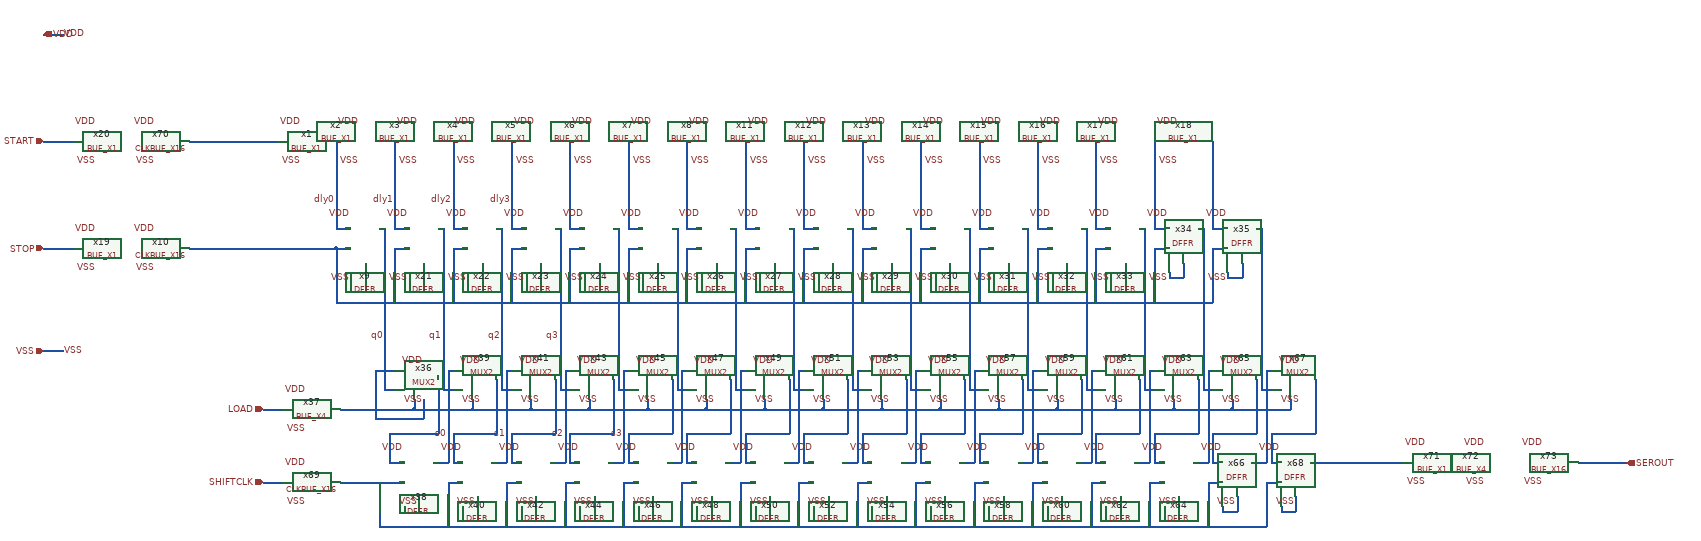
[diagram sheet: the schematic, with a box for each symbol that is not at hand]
v {xschem version=3.4.8RC file_version=1.2}
G {}
K {}
V {}
S {}
E {}
N -480 0 -420 0 {lab=START}
N -480 220 -420 220 {lab=STOP}
N 120 220 150 220 {lab=#net1}
N 120 -0 120 180 {lab=dly0}
N 120 180 150 180 {lab=dly0}
N 240 0 240 180 {lab=dly1}
N 240 180 270 180 {lab=dly1}
N 360 0 360 180 {lab=dly2}
N 360 180 390 180 {lab=dly2}
N 480 0 480 180 {lab=dly3}
N 480 180 510 180 {lab=dly3}
N 600 0 600 180 {lab=#net2}
N 600 180 630 180 {lab=#net2}
N 720 0 720 180 {lab=#net3}
N 720 180 750 180 {lab=#net3}
N 840 0 840 180 {lab=#net4}
N 840 180 870 180 {lab=#net4}
N 960 0 960 180 {lab=#net5}
N 960 180 990 180 {lab=#net5}
N 1080 0 1080 180 {lab=#net6}
N 1080 180 1110 180 {lab=#net6}
N 1200 0 1200 180 {lab=#net7}
N 1200 180 1230 180 {lab=#net7}
N 1320 0 1320 180 {lab=#net8}
N 1320 180 1350 180 {lab=#net8}
N 1440 0 1440 180 {lab=#net9}
N 1440 180 1470 180 {lab=#net9}
N 1560 0 1560 180 {lab=#net10}
N 1560 180 1590 180 {lab=#net10}
N 1680 0 1680 180 {lab=#net11}
N 1680 180 1710 180 {lab=#net11}
N 1800 0 1800 180 {lab=#net12}
N 1800 180 1830 180 {lab=#net12}
N 720 220 750 220 {lab=#net1}
N 720 220 720 330 {lab=#net1}
N 840 220 870 220 {lab=#net1}
N 840 220 840 330 {lab=#net1}
N 960 220 990 220 {lab=#net1}
N 960 220 960 330 {lab=#net1}
N 1080 220 1110 220 {lab=#net1}
N 1080 220 1080 330 {lab=#net1}
N 1200 220 1230 220 {lab=#net1}
N 1200 220 1200 330 {lab=#net1}
N 1320 220 1350 220 {lab=#net1}
N 1320 220 1320 330 {lab=#net1}
N 1440 220 1470 220 {lab=#net1}
N 1440 220 1440 330 {lab=#net1}
N 1560 220 1590 220 {lab=#net1}
N 1560 220 1560 330 {lab=#net1}
N 240 220 270 220 {lab=#net1}
N 240 220 240 330 {lab=#net1}
N 360 220 390 220 {lab=#net1}
N 360 220 360 330 {lab=#net1}
N 480 220 510 220 {lab=#net1}
N 480 220 480 330 {lab=#net1}
N 600 220 630 220 {lab=#net1}
N 600 220 600 330 {lab=#net1}
N 1680 220 1710 220 {lab=#net1}
N 1680 220 1680 330 {lab=#net1}
N 1800 220 1830 220 {lab=#net1}
N 1800 220 1800 330 {lab=#net1}
N 1920 0 1920 180 {lab=#net13}
N 1920 180 1950 180 {lab=#net13}
N 1920 220 1950 220 {lab=#net1}
N 1920 220 1920 330 {lab=#net1}
N 120 220 120 330 {lab=#net1}
N 120 330 1920 330 {lab=#net1}
N -180 220 120 220 {lab=#net1}
N 300 530 300 570 {lab=VSS}
N 200 570 300 570 {lab=VSS}
N 200 470 200 570 {lab=VSS}
N 200 470 240 470 {lab=VSS}
N 210 180 220 180 {lab=q0}
N 220 180 220 400 {lab=q0}
N 220 400 220 510 {lab=q0}
N 220 510 240 510 {lab=q0}
N 280 530 280 550 {lab=#net14}
N -30 550 10 550 {lab=LOAD}
N 130 550 280 550 {lab=#net14}
N 330 490 330 600 {lab=#net15}
N 230 600 330 600 {lab=#net15}
N 230 600 230 660 {lab=#net15}
N 230 660 260 660 {lab=#net15}
N 400 530 400 550 {lab=#net14}
N 330 180 340 180 {lab=q1}
N 340 180 340 510 {lab=q1}
N 350 700 380 700 {lab=#net16}
N 350 700 350 770 {lab=#net16}
N 350 770 350 790 {lab=#net16}
N 210 700 210 790 {lab=#net16}
N 340 510 360 510 {lab=q1}
N 350 470 360 470 {lab=s0}
N 350 470 350 660 {lab=s0}
N 320 660 350 660 {lab=s0}
N 280 550 400 550 {lab=#net14}
N 570 490 570 600 {lab=#net17}
N 520 530 520 550 {lab=#net14}
N 450 180 460 180 {lab=q2}
N 460 180 460 510 {lab=q2}
N 470 700 500 700 {lab=#net16}
N 470 700 470 770 {lab=#net16}
N 470 770 470 790 {lab=#net16}
N 480 660 500 660 {lab=#net17}
N 480 600 480 660 {lab=#net17}
N 480 600 570 600 {lab=#net17}
N 460 510 480 510 {lab=q2}
N 470 470 480 470 {lab=s1}
N 470 470 470 660 {lab=s1}
N 440 660 470 660 {lab=s1}
N 400 550 520 550 {lab=#net14}
N 690 490 690 600 {lab=#net18}
N 640 530 640 550 {lab=#net14}
N 570 180 580 180 {lab=q3}
N 580 180 580 510 {lab=q3}
N 590 700 620 700 {lab=#net16}
N 590 700 590 770 {lab=#net16}
N 590 770 590 790 {lab=#net16}
N 600 660 620 660 {lab=#net18}
N 600 600 600 660 {lab=#net18}
N 600 600 690 600 {lab=#net18}
N 580 510 600 510 {lab=q3}
N 590 470 600 470 {lab=s2}
N 590 470 590 660 {lab=s2}
N 560 660 590 660 {lab=s2}
N 520 550 640 550 {lab=#net14}
N 810 490 810 600 {lab=#net19}
N 760 530 760 550 {lab=#net14}
N 690 180 700 180 {lab=#net20}
N 700 180 700 510 {lab=#net20}
N 710 700 740 700 {lab=#net16}
N 710 700 710 770 {lab=#net16}
N 710 770 710 790 {lab=#net16}
N 720 660 740 660 {lab=#net19}
N 720 600 720 660 {lab=#net19}
N 720 600 810 600 {lab=#net19}
N 700 510 720 510 {lab=#net20}
N 710 470 720 470 {lab=s3}
N 710 470 710 660 {lab=s3}
N 680 660 710 660 {lab=s3}
N 640 550 760 550 {lab=#net14}
N 930 490 930 600 {lab=#net21}
N 880 530 880 550 {lab=#net14}
N 810 180 820 180 {lab=#net22}
N 820 180 820 510 {lab=#net22}
N 830 700 860 700 {lab=#net16}
N 830 700 830 770 {lab=#net16}
N 830 770 830 790 {lab=#net16}
N 840 660 860 660 {lab=#net21}
N 840 600 840 660 {lab=#net21}
N 840 600 930 600 {lab=#net21}
N 820 510 840 510 {lab=#net22}
N 830 470 840 470 {lab=#net23}
N 830 470 830 660 {lab=#net23}
N 800 660 830 660 {lab=#net23}
N 760 550 880 550 {lab=#net14}
N 1050 490 1050 600 {lab=#net24}
N 1000 530 1000 550 {lab=#net14}
N 930 180 940 180 {lab=#net25}
N 940 180 940 510 {lab=#net25}
N 950 700 980 700 {lab=#net16}
N 950 700 950 770 {lab=#net16}
N 950 770 950 790 {lab=#net16}
N 960 660 980 660 {lab=#net24}
N 960 600 960 660 {lab=#net24}
N 960 600 1050 600 {lab=#net24}
N 940 510 960 510 {lab=#net25}
N 950 470 960 470 {lab=#net26}
N 950 470 950 660 {lab=#net26}
N 920 660 950 660 {lab=#net26}
N 880 550 1000 550 {lab=#net14}
N 1170 490 1170 600 {lab=#net27}
N 1120 530 1120 550 {lab=#net14}
N 1050 180 1060 180 {lab=#net28}
N 1060 180 1060 510 {lab=#net28}
N 1070 700 1100 700 {lab=#net16}
N 1070 700 1070 770 {lab=#net16}
N 1070 770 1070 790 {lab=#net16}
N 1080 660 1100 660 {lab=#net27}
N 1080 600 1080 660 {lab=#net27}
N 1080 600 1170 600 {lab=#net27}
N 1060 510 1080 510 {lab=#net28}
N 1070 470 1080 470 {lab=#net29}
N 1070 470 1070 660 {lab=#net29}
N 1040 660 1070 660 {lab=#net29}
N 1000 550 1120 550 {lab=#net14}
N 1290 490 1290 600 {lab=#net30}
N 1240 530 1240 550 {lab=#net14}
N 1170 180 1180 180 {lab=#net31}
N 1180 180 1180 510 {lab=#net31}
N 1190 700 1220 700 {lab=#net16}
N 1190 700 1190 770 {lab=#net16}
N 1190 770 1190 790 {lab=#net16}
N 1200 660 1220 660 {lab=#net30}
N 1200 600 1200 660 {lab=#net30}
N 1200 600 1290 600 {lab=#net30}
N 1180 510 1200 510 {lab=#net31}
N 1190 470 1200 470 {lab=#net32}
N 1190 470 1190 660 {lab=#net32}
N 1160 660 1190 660 {lab=#net32}
N 1120 550 1240 550 {lab=#net14}
N 1410 490 1410 600 {lab=#net33}
N 1360 530 1360 550 {lab=#net14}
N 1290 180 1300 180 {lab=#net34}
N 1300 180 1300 510 {lab=#net34}
N 1310 700 1340 700 {lab=#net16}
N 1310 700 1310 770 {lab=#net16}
N 1310 770 1310 790 {lab=#net16}
N 1320 660 1340 660 {lab=#net33}
N 1320 600 1320 660 {lab=#net33}
N 1320 600 1410 600 {lab=#net33}
N 1300 510 1320 510 {lab=#net34}
N 1310 470 1320 470 {lab=#net35}
N 1310 470 1310 660 {lab=#net35}
N 1280 660 1310 660 {lab=#net35}
N 1240 550 1360 550 {lab=#net14}
N 1530 490 1530 600 {lab=#net36}
N 1480 530 1480 550 {lab=#net14}
N 1410 180 1420 180 {lab=#net37}
N 1420 180 1420 510 {lab=#net37}
N 1430 700 1460 700 {lab=#net16}
N 1430 700 1430 770 {lab=#net16}
N 1430 770 1430 790 {lab=#net16}
N 1440 660 1460 660 {lab=#net36}
N 1440 600 1440 660 {lab=#net36}
N 1440 600 1530 600 {lab=#net36}
N 1420 510 1440 510 {lab=#net37}
N 1430 470 1440 470 {lab=#net38}
N 1430 470 1430 660 {lab=#net38}
N 1400 660 1430 660 {lab=#net38}
N 1360 550 1480 550 {lab=#net14}
N 1650 490 1650 600 {lab=#net39}
N 1600 530 1600 550 {lab=#net14}
N 1530 180 1540 180 {lab=#net40}
N 1540 180 1540 510 {lab=#net40}
N 1550 700 1580 700 {lab=#net16}
N 1550 700 1550 770 {lab=#net16}
N 1550 770 1550 790 {lab=#net16}
N 1560 660 1580 660 {lab=#net39}
N 1560 600 1560 660 {lab=#net39}
N 1560 600 1650 600 {lab=#net39}
N 1540 510 1560 510 {lab=#net40}
N 1550 470 1560 470 {lab=#net41}
N 1550 470 1550 660 {lab=#net41}
N 1520 660 1550 660 {lab=#net41}
N 1480 550 1600 550 {lab=#net14}
N 1770 490 1770 600 {lab=#net42}
N 1720 530 1720 550 {lab=#net14}
N 1650 180 1660 180 {lab=#net43}
N 1660 180 1660 510 {lab=#net43}
N 1670 700 1700 700 {lab=#net16}
N 1670 700 1670 770 {lab=#net16}
N 1670 770 1670 790 {lab=#net16}
N 1680 660 1700 660 {lab=#net42}
N 1680 600 1680 660 {lab=#net42}
N 1680 600 1770 600 {lab=#net42}
N 1660 510 1680 510 {lab=#net43}
N 1670 470 1680 470 {lab=#net44}
N 1670 470 1670 660 {lab=#net44}
N 1640 660 1670 660 {lab=#net44}
N 1600 550 1720 550 {lab=#net14}
N 1890 490 1890 600 {lab=#net45}
N 1840 530 1840 550 {lab=#net14}
N 1770 180 1780 180 {lab=#net46}
N 1780 180 1780 510 {lab=#net46}
N 1790 700 1820 700 {lab=#net16}
N 1790 700 1790 770 {lab=#net16}
N 1790 770 1790 790 {lab=#net16}
N 1800 660 1820 660 {lab=#net45}
N 1800 600 1800 660 {lab=#net45}
N 1800 600 1890 600 {lab=#net45}
N 1780 510 1800 510 {lab=#net46}
N 1790 470 1800 470 {lab=#net47}
N 1790 470 1790 660 {lab=#net47}
N 1760 660 1790 660 {lab=#net47}
N 1720 550 1840 550 {lab=#net14}
N 2010 490 2010 600 {lab=#net48}
N 1960 530 1960 550 {lab=#net14}
N 1890 180 1900 180 {lab=#net49}
N 1900 180 1900 510 {lab=#net49}
N 1910 700 1940 700 {lab=#net16}
N 1910 700 1910 770 {lab=#net16}
N 1910 770 1910 790 {lab=#net16}
N 1920 660 1940 660 {lab=#net48}
N 1920 600 1920 660 {lab=#net48}
N 1920 600 2010 600 {lab=#net48}
N 1900 510 1920 510 {lab=#net49}
N 1910 470 1920 470 {lab=#net50}
N 1910 470 1910 660 {lab=#net50}
N 1880 660 1910 660 {lab=#net50}
N 1840 550 1960 550 {lab=#net14}
N 2130 490 2130 600 {lab=#net51}
N 2080 530 2080 550 {lab=#net14}
N 2010 180 2020 180 {lab=#net52}
N 2020 180 2020 510 {lab=#net52}
N 2030 700 2060 700 {lab=#net16}
N 2030 700 2030 770 {lab=#net16}
N 2030 770 2030 790 {lab=#net16}
N 2040 660 2060 660 {lab=#net51}
N 2040 600 2040 660 {lab=#net51}
N 2040 600 2130 600 {lab=#net51}
N 2020 510 2040 510 {lab=#net52}
N 2030 470 2040 470 {lab=#net53}
N 2030 470 2030 660 {lab=#net53}
N 2000 660 2030 660 {lab=#net53}
N 1960 550 2080 550 {lab=#net14}
N 210 790 2030 790 {lab=#net16}
N 450 490 450 600 {lab=#net54}
N 360 600 450 600 {lab=#net54}
N 360 600 360 660 {lab=#net54}
N 360 660 380 660 {lab=#net54}
N 140 700 260 700 {lab=#net16}
N 130 700 140 700 {lab=#net16}
N -30 700 10 700 {lab=SHIFTCLK}
N 2120 660 2310 660 {lab=#net55}
N 2670 660 2770 660 {lab=SEROUT}
N -180 0 0 0 {lab=#net56}
N 180 250 180 280 {lab=VSS}
N 150 280 180 280 {lab=VSS}
N 150 270 150 280 {lab=VSS}
N 300 250 300 280 {lab=VSS}
N 270 280 300 280 {lab=VSS}
N 270 270 270 280 {lab=VSS}
N 420 250 420 280 {lab=VSS}
N 390 280 420 280 {lab=VSS}
N 390 270 390 280 {lab=VSS}
N 540 250 540 280 {lab=VSS}
N 510 280 540 280 {lab=VSS}
N 510 270 510 280 {lab=VSS}
N 660 250 660 280 {lab=VSS}
N 630 280 660 280 {lab=VSS}
N 630 270 630 280 {lab=VSS}
N 780 250 780 280 {lab=VSS}
N 750 280 780 280 {lab=VSS}
N 750 270 750 280 {lab=VSS}
N 900 250 900 280 {lab=VSS}
N 870 280 900 280 {lab=VSS}
N 870 270 870 280 {lab=VSS}
N 1020 250 1020 280 {lab=VSS}
N 990 280 1020 280 {lab=VSS}
N 990 270 990 280 {lab=VSS}
N 1140 250 1140 280 {lab=VSS}
N 1110 280 1140 280 {lab=VSS}
N 1110 270 1110 280 {lab=VSS}
N 1260 250 1260 280 {lab=VSS}
N 1230 280 1260 280 {lab=VSS}
N 1230 270 1230 280 {lab=VSS}
N 1380 250 1380 280 {lab=VSS}
N 1350 280 1380 280 {lab=VSS}
N 1350 270 1350 280 {lab=VSS}
N 1500 250 1500 280 {lab=VSS}
N 1470 280 1500 280 {lab=VSS}
N 1470 270 1470 280 {lab=VSS}
N 1620 250 1620 280 {lab=VSS}
N 1590 280 1620 280 {lab=VSS}
N 1590 270 1590 280 {lab=VSS}
N 1740 250 1740 280 {lab=VSS}
N 1710 280 1740 280 {lab=VSS}
N 1710 270 1710 280 {lab=VSS}
N 1860 250 1860 280 {lab=VSS}
N 1830 280 1860 280 {lab=VSS}
N 1830 270 1830 280 {lab=VSS}
N 1980 250 1980 280 {lab=VSS}
N 1950 280 1980 280 {lab=VSS}
N 1950 270 1950 280 {lab=VSS}
N 290 730 290 760 {lab=VSS}
N 260 760 290 760 {lab=VSS}
N 260 750 260 760 {lab=VSS}
N 410 730 410 760 {lab=VSS}
N 380 760 410 760 {lab=VSS}
N 380 750 380 760 {lab=VSS}
N 530 730 530 760 {lab=VSS}
N 500 760 530 760 {lab=VSS}
N 500 750 500 760 {lab=VSS}
N 650 730 650 760 {lab=VSS}
N 620 760 650 760 {lab=VSS}
N 620 750 620 760 {lab=VSS}
N 770 730 770 760 {lab=VSS}
N 740 760 770 760 {lab=VSS}
N 740 750 740 760 {lab=VSS}
N 890 730 890 760 {lab=VSS}
N 860 760 890 760 {lab=VSS}
N 860 750 860 760 {lab=VSS}
N 1010 730 1010 760 {lab=VSS}
N 980 760 1010 760 {lab=VSS}
N 980 750 980 760 {lab=VSS}
N 1130 730 1130 760 {lab=VSS}
N 1100 760 1130 760 {lab=VSS}
N 1100 750 1100 760 {lab=VSS}
N 1250 730 1250 760 {lab=VSS}
N 1220 760 1250 760 {lab=VSS}
N 1220 750 1220 760 {lab=VSS}
N 1370 730 1370 760 {lab=VSS}
N 1340 760 1370 760 {lab=VSS}
N 1340 750 1340 760 {lab=VSS}
N 1490 730 1490 760 {lab=VSS}
N 1460 760 1490 760 {lab=VSS}
N 1460 750 1460 760 {lab=VSS}
N 1610 730 1610 760 {lab=VSS}
N 1580 760 1610 760 {lab=VSS}
N 1580 750 1580 760 {lab=VSS}
N 1730 730 1730 760 {lab=VSS}
N 1700 760 1730 760 {lab=VSS}
N 1700 750 1700 760 {lab=VSS}
N 1850 730 1850 760 {lab=VSS}
N 1820 760 1850 760 {lab=VSS}
N 1820 750 1820 760 {lab=VSS}
N 1970 730 1970 760 {lab=VSS}
N 1940 760 1970 760 {lab=VSS}
N 1940 750 1940 760 {lab=VSS}
N 2090 730 2090 760 {lab=VSS}
N 2060 760 2090 760 {lab=VSS}
N 2060 750 2060 760 {lab=VSS}
N -480 -220 -440 -220 {lab=VDD}
N -480 430 -440 430 {lab=VSS}
C {TR-1um_5_stdcell/BUF_X1.sym} 20 0 0 0 {name=x1}
C {TR-1um_5_stdcell/BUF_X1.sym} 140 0 0 0 {name=x2}
C {TR-1um_5_stdcell/BUF_X1.sym} 260 0 0 0 {name=x3}
C {TR-1um_5_stdcell/BUF_X1.sym} 380 0 0 0 {name=x4}
C {TR-1um_5_stdcell/BUF_X1.sym} 500 0 0 0 {name=x5}
C {TR-1um_5_stdcell/BUF_X1.sym} 620 0 0 0 {name=x6}
C {TR-1um_5_stdcell/BUF_X1.sym} 740 0 0 0 {name=x7}
C {TR-1um_5_stdcell/BUF_X1.sym} 860 0 0 0 {name=x8}
C {TR-1um_5_stdcell/DFFR.sym} 180 210 0 0 {name=x9}
C {TR-1um_5_stdcell/CLKBUF_X16.sym} -280 220 0 0 {name=x10}
C {TR-1um_5_stdcell/BUF_X1.sym} 980 0 0 0 {name=x11}
C {TR-1um_5_stdcell/BUF_X1.sym} 1100 0 0 0 {name=x12}
C {TR-1um_5_stdcell/BUF_X1.sym} 1220 0 0 0 {name=x13}
C {TR-1um_5_stdcell/BUF_X1.sym} 1340 0 0 0 {name=x14}
C {TR-1um_5_stdcell/BUF_X1.sym} 1460 0 0 0 {name=x15}
C {TR-1um_5_stdcell/BUF_X1.sym} 1580 0 0 0 {name=x16}
C {TR-1um_5_stdcell/BUF_X1.sym} 1700 0 0 0 {name=x17}
C {TR-1um_5_stdcell/BUF_X1.sym} 1820 0 0 0 {name=x18}
C {TR-1um_5_stdcell/BUF_X1.sym} -400 220 0 0 {name=x19}
C {TR-1um_5_stdcell/BUF_X1.sym} -400 0 0 0 {name=x20}
C {devices/ipin.sym} -480 0 0 0 {name=p10 lab=START}
C {devices/ipin.sym} -480 220 0 0 {name=p1 lab=STOP}
C {TR-1um_5_stdcell/DFFR.sym} 300 210 0 0 {name=x21}
C {TR-1um_5_stdcell/DFFR.sym} 420 210 0 0 {name=x22}
C {TR-1um_5_stdcell/DFFR.sym} 540 210 0 0 {name=x23}
C {TR-1um_5_stdcell/DFFR.sym} 660 210 0 0 {name=x24}
C {TR-1um_5_stdcell/DFFR.sym} 780 210 0 0 {name=x25}
C {TR-1um_5_stdcell/DFFR.sym} 900 210 0 0 {name=x26}
C {TR-1um_5_stdcell/DFFR.sym} 1020 210 0 0 {name=x27}
C {TR-1um_5_stdcell/DFFR.sym} 1140 210 0 0 {name=x28}
C {TR-1um_5_stdcell/DFFR.sym} 1260 210 0 0 {name=x29}
C {TR-1um_5_stdcell/DFFR.sym} 1380 210 0 0 {name=x30}
C {TR-1um_5_stdcell/DFFR.sym} 1500 210 0 0 {name=x31}
C {TR-1um_5_stdcell/DFFR.sym} 1620 210 0 0 {name=x32}
C {TR-1um_5_stdcell/DFFR.sym} 1740 210 0 0 {name=x33}
C {TR-1um_5_stdcell/DFFR.sym} 1860 210 0 0 {name=x34}
C {TR-1um_5_stdcell/DFFR.sym} 1980 210 0 0 {name=x35}
C {devices/iopin.sym} -480 -220 0 1 {name=p17 lab=VDD}
C {devices/iopin.sym} -480 430 2 0 {name=p6 lab=VSS}
C {devices/ipin.sym} -30 700 0 0 {name=p2 lab=SHIFTCLK}
C {devices/opin.sym} 2770 660 0 0 {name=p16 lab=SEROUT}
C {TR-1um_5_stdcell/MUX2.sym} 260 490 0 0 {name=x36}
C {devices/ipin.sym} -30 550 0 0 {name=p3 lab=LOAD}
C {TR-1um_5_stdcell/DFFR.sym} 290 690 0 0 {name=x38}
C {TR-1um_5_stdcell/MUX2.sym} 380 490 0 0 {name=x39}
C {TR-1um_5_stdcell/DFFR.sym} 410 690 0 0 {name=x40}
C {TR-1um_5_stdcell/MUX2.sym} 500 490 0 0 {name=x41}
C {TR-1um_5_stdcell/DFFR.sym} 530 690 0 0 {name=x42}
C {TR-1um_5_stdcell/MUX2.sym} 620 490 0 0 {name=x43}
C {TR-1um_5_stdcell/DFFR.sym} 650 690 0 0 {name=x44}
C {TR-1um_5_stdcell/MUX2.sym} 740 490 0 0 {name=x45}
C {TR-1um_5_stdcell/DFFR.sym} 770 690 0 0 {name=x46}
C {TR-1um_5_stdcell/MUX2.sym} 860 490 0 0 {name=x47}
C {TR-1um_5_stdcell/DFFR.sym} 890 690 0 0 {name=x48}
C {TR-1um_5_stdcell/MUX2.sym} 980 490 0 0 {name=x49}
C {TR-1um_5_stdcell/DFFR.sym} 1010 690 0 0 {name=x50}
C {TR-1um_5_stdcell/MUX2.sym} 1100 490 0 0 {name=x51}
C {TR-1um_5_stdcell/DFFR.sym} 1130 690 0 0 {name=x52}
C {TR-1um_5_stdcell/MUX2.sym} 1220 490 0 0 {name=x53}
C {TR-1um_5_stdcell/DFFR.sym} 1250 690 0 0 {name=x54}
C {TR-1um_5_stdcell/MUX2.sym} 1340 490 0 0 {name=x55}
C {TR-1um_5_stdcell/DFFR.sym} 1370 690 0 0 {name=x56}
C {TR-1um_5_stdcell/MUX2.sym} 1460 490 0 0 {name=x57}
C {TR-1um_5_stdcell/DFFR.sym} 1490 690 0 0 {name=x58}
C {TR-1um_5_stdcell/MUX2.sym} 1580 490 0 0 {name=x59}
C {TR-1um_5_stdcell/DFFR.sym} 1610 690 0 0 {name=x60}
C {TR-1um_5_stdcell/MUX2.sym} 1700 490 0 0 {name=x61}
C {TR-1um_5_stdcell/DFFR.sym} 1730 690 0 0 {name=x62}
C {TR-1um_5_stdcell/MUX2.sym} 1820 490 0 0 {name=x63}
C {TR-1um_5_stdcell/DFFR.sym} 1850 690 0 0 {name=x64}
C {TR-1um_5_stdcell/MUX2.sym} 1940 490 0 0 {name=x65}
C {TR-1um_5_stdcell/DFFR.sym} 1970 690 0 0 {name=x66}
C {TR-1um_5_stdcell/MUX2.sym} 2060 490 0 0 {name=x67}
C {TR-1um_5_stdcell/DFFR.sym} 2090 690 0 0 {name=x68}
C {TR-1um_5_stdcell/BUF_X4.sym} 30 550 0 0 {name=x37}
C {TR-1um_5_stdcell/CLKBUF_X16.sym} 30 700 0 0 {name=x69}
C {TR-1um_5_stdcell/CLKBUF_X16.sym} -280 0 0 0 {name=x70}
C {TR-1um_5_stdcell/BUF_X1.sym} 2330 660 0 0 {name=x71}
C {TR-1um_5_stdcell/BUF_X4.sym} 2450 660 0 0 {name=x72}
C {TR-1um_5_stdcell/BUF_X16.sym} 2570 660 0 0 {name=x73}
C {devices/lab_pin.sym} -440 -220 2 0 {name=p4 sig_type=std_logic lab=VDD}
C {devices/lab_pin.sym} -440 430 2 0 {name=p77 sig_type=std_logic lab=VSS}
C {devices/lab_pin.sym} -370 -40 1 0 {name=p146 sig_type=std_logic lab=VDD}
C {devices/lab_pin.sym} -250 -40 1 0 {name=p147 sig_type=std_logic lab=VDD}
C {devices/lab_pin.sym} -370 40 3 0 {name=p148 sig_type=std_logic lab=VSS}
C {devices/lab_pin.sym} -250 40 3 0 {name=p149 sig_type=std_logic lab=VSS}
C {devices/lab_pin.sym} -370 180 1 0 {name=p7 sig_type=std_logic lab=VDD}
C {devices/lab_pin.sym} -250 180 1 0 {name=p78 sig_type=std_logic lab=VDD}
C {devices/lab_pin.sym} -370 260 3 0 {name=p150 sig_type=std_logic lab=VSS}
C {devices/lab_pin.sym} -250 260 3 0 {name=p151 sig_type=std_logic lab=VSS}
C {devices/lab_pin.sym} 2360 620 1 0 {name=p152 sig_type=std_logic lab=VDD}
C {devices/lab_pin.sym} 2360 700 3 0 {name=p153 sig_type=std_logic lab=VSS}
C {devices/lab_pin.sym} 2480 620 1 0 {name=p74 sig_type=std_logic lab=VDD}
C {devices/lab_pin.sym} 2480 700 3 0 {name=p75 sig_type=std_logic lab=VSS}
C {devices/lab_pin.sym} 2600 620 1 0 {name=p76 sig_type=std_logic lab=VDD}
C {devices/lab_pin.sym} 2600 700 3 0 {name=p143 sig_type=std_logic lab=VSS}
C {devices/lab_pin.sym} 50 -40 1 0 {name=p5 sig_type=std_logic lab=VDD}
C {devices/lab_pin.sym} 170 -40 1 0 {name=p9 sig_type=std_logic lab=VDD}
C {devices/lab_pin.sym} 290 -40 1 0 {name=p11 sig_type=std_logic lab=VDD}
C {devices/lab_pin.sym} 410 -40 1 0 {name=p12 sig_type=std_logic lab=VDD}
C {devices/lab_pin.sym} 530 -40 1 0 {name=p13 sig_type=std_logic lab=VDD}
C {devices/lab_pin.sym} 650 -40 1 0 {name=p14 sig_type=std_logic lab=VDD}
C {devices/lab_pin.sym} 770 -40 1 0 {name=p15 sig_type=std_logic lab=VDD}
C {devices/lab_pin.sym} 890 -40 1 0 {name=p18 sig_type=std_logic lab=VDD}
C {devices/lab_pin.sym} 1490 -40 1 0 {name=p19 sig_type=std_logic lab=VDD}
C {devices/lab_pin.sym} 1610 -40 1 0 {name=p20 sig_type=std_logic lab=VDD}
C {devices/lab_pin.sym} 1730 -40 1 0 {name=p21 sig_type=std_logic lab=VDD}
C {devices/lab_pin.sym} 1850 -40 1 0 {name=p22 sig_type=std_logic lab=VDD}
C {devices/lab_pin.sym} 1010 -40 1 0 {name=p23 sig_type=std_logic lab=VDD}
C {devices/lab_pin.sym} 1130 -40 1 0 {name=p24 sig_type=std_logic lab=VDD}
C {devices/lab_pin.sym} 1250 -40 1 0 {name=p25 sig_type=std_logic lab=VDD}
C {devices/lab_pin.sym} 1370 -40 1 0 {name=p26 sig_type=std_logic lab=VDD}
C {devices/lab_pin.sym} 1950 150 1 0 {name=p38 sig_type=std_logic lab=VDD}
C {devices/lab_pin.sym} 150 280 3 0 {name=p95 sig_type=std_logic lab=VSS}
C {devices/lab_pin.sym} 270 280 3 0 {name=p96 sig_type=std_logic lab=VSS}
C {devices/lab_pin.sym} 390 280 3 0 {name=p97 sig_type=std_logic lab=VSS}
C {devices/lab_pin.sym} 510 280 3 0 {name=p98 sig_type=std_logic lab=VSS}
C {devices/lab_pin.sym} 630 280 3 0 {name=p99 sig_type=std_logic lab=VSS}
C {devices/lab_pin.sym} 750 280 3 0 {name=p100 sig_type=std_logic lab=VSS}
C {devices/lab_pin.sym} 870 280 3 0 {name=p101 sig_type=std_logic lab=VSS}
C {devices/lab_pin.sym} 990 280 3 0 {name=p102 sig_type=std_logic lab=VSS}
C {devices/lab_pin.sym} 1110 280 3 0 {name=p103 sig_type=std_logic lab=VSS}
C {devices/lab_pin.sym} 1230 280 3 0 {name=p104 sig_type=std_logic lab=VSS}
C {devices/lab_pin.sym} 1350 280 3 0 {name=p105 sig_type=std_logic lab=VSS}
C {devices/lab_pin.sym} 1470 280 3 0 {name=p106 sig_type=std_logic lab=VSS}
C {devices/lab_pin.sym} 1590 280 3 0 {name=p107 sig_type=std_logic lab=VSS}
C {devices/lab_pin.sym} 1710 280 3 0 {name=p108 sig_type=std_logic lab=VSS}
C {devices/lab_pin.sym} 1830 280 3 0 {name=p109 sig_type=std_logic lab=VSS}
C {devices/lab_pin.sym} 1950 280 3 0 {name=p110 sig_type=std_logic lab=VSS}
C {devices/lab_pin.sym} 300 450 1 0 {name=p42 sig_type=std_logic lab=VDD}
C {devices/lab_pin.sym} 420 450 1 0 {name=p43 sig_type=std_logic lab=VDD}
C {devices/lab_pin.sym} 540 450 1 0 {name=p44 sig_type=std_logic lab=VDD}
C {devices/lab_pin.sym} 660 450 1 0 {name=p45 sig_type=std_logic lab=VDD}
C {devices/lab_pin.sym} 780 450 1 0 {name=p46 sig_type=std_logic lab=VDD}
C {devices/lab_pin.sym} 900 450 1 0 {name=p47 sig_type=std_logic lab=VDD}
C {devices/lab_pin.sym} 1020 450 1 0 {name=p48 sig_type=std_logic lab=VDD}
C {devices/lab_pin.sym} 1140 450 1 0 {name=p49 sig_type=std_logic lab=VDD}
C {devices/lab_pin.sym} 1740 450 1 0 {name=p50 sig_type=std_logic lab=VDD}
C {devices/lab_pin.sym} 1860 450 1 0 {name=p51 sig_type=std_logic lab=VDD}
C {devices/lab_pin.sym} 1980 450 1 0 {name=p52 sig_type=std_logic lab=VDD}
C {devices/lab_pin.sym} 2100 450 1 0 {name=p53 sig_type=std_logic lab=VDD}
C {devices/lab_pin.sym} 1260 450 1 0 {name=p54 sig_type=std_logic lab=VDD}
C {devices/lab_pin.sym} 1380 450 1 0 {name=p55 sig_type=std_logic lab=VDD}
C {devices/lab_pin.sym} 1500 450 1 0 {name=p56 sig_type=std_logic lab=VDD}
C {devices/lab_pin.sym} 1620 450 1 0 {name=p144 sig_type=std_logic lab=VDD}
C {devices/lab_pin.sym} 60 510 1 0 {name=p57 sig_type=std_logic lab=VDD}
C {devices/lab_pin.sym} 60 590 3 0 {name=p145 sig_type=std_logic lab=VSS}
C {devices/lab_pin.sym} 60 660 1 0 {name=p154 sig_type=std_logic lab=VDD}
C {devices/lab_pin.sym} 60 740 3 0 {name=p155 sig_type=std_logic lab=VSS}
C {devices/lab_pin.sym} 50 40 3 0 {name=p58 sig_type=std_logic lab=VSS}
C {devices/lab_pin.sym} 150 150 1 0 {name=p59 sig_type=std_logic lab=VDD}
C {devices/lab_pin.sym} 270 150 1 0 {name=p60 sig_type=std_logic lab=VDD}
C {devices/lab_pin.sym} 390 150 1 0 {name=p61 sig_type=std_logic lab=VDD}
C {devices/lab_pin.sym} 510 150 1 0 {name=p62 sig_type=std_logic lab=VDD}
C {devices/lab_pin.sym} 630 150 1 0 {name=p63 sig_type=std_logic lab=VDD}
C {devices/lab_pin.sym} 750 150 1 0 {name=p64 sig_type=std_logic lab=VDD}
C {devices/lab_pin.sym} 870 150 1 0 {name=p65 sig_type=std_logic lab=VDD}
C {devices/lab_pin.sym} 990 150 1 0 {name=p66 sig_type=std_logic lab=VDD}
C {devices/lab_pin.sym} 1590 150 1 0 {name=p67 sig_type=std_logic lab=VDD}
C {devices/lab_pin.sym} 1710 150 1 0 {name=p68 sig_type=std_logic lab=VDD}
C {devices/lab_pin.sym} 1830 150 1 0 {name=p69 sig_type=std_logic lab=VDD}
C {devices/lab_pin.sym} 1110 150 1 0 {name=p70 sig_type=std_logic lab=VDD}
C {devices/lab_pin.sym} 1230 150 1 0 {name=p71 sig_type=std_logic lab=VDD}
C {devices/lab_pin.sym} 1350 150 1 0 {name=p72 sig_type=std_logic lab=VDD}
C {devices/lab_pin.sym} 1470 150 1 0 {name=p73 sig_type=std_logic lab=VDD}
C {devices/lab_pin.sym} 170 40 3 0 {name=p111 sig_type=std_logic lab=VSS}
C {devices/lab_pin.sym} 290 40 3 0 {name=p112 sig_type=std_logic lab=VSS}
C {devices/lab_pin.sym} 410 40 3 0 {name=p113 sig_type=std_logic lab=VSS}
C {devices/lab_pin.sym} 530 40 3 0 {name=p114 sig_type=std_logic lab=VSS}
C {devices/lab_pin.sym} 650 40 3 0 {name=p115 sig_type=std_logic lab=VSS}
C {devices/lab_pin.sym} 770 40 3 0 {name=p116 sig_type=std_logic lab=VSS}
C {devices/lab_pin.sym} 890 40 3 0 {name=p117 sig_type=std_logic lab=VSS}
C {devices/lab_pin.sym} 1010 40 3 0 {name=p118 sig_type=std_logic lab=VSS}
C {devices/lab_pin.sym} 1130 40 3 0 {name=p119 sig_type=std_logic lab=VSS}
C {devices/lab_pin.sym} 1250 40 3 0 {name=p120 sig_type=std_logic lab=VSS}
C {devices/lab_pin.sym} 1370 40 3 0 {name=p121 sig_type=std_logic lab=VSS}
C {devices/lab_pin.sym} 1490 40 3 0 {name=p122 sig_type=std_logic lab=VSS}
C {devices/lab_pin.sym} 1610 40 3 0 {name=p123 sig_type=std_logic lab=VSS}
C {devices/lab_pin.sym} 1730 40 3 0 {name=p124 sig_type=std_logic lab=VSS}
C {devices/lab_pin.sym} 1850 40 3 0 {name=p125 sig_type=std_logic lab=VSS}
C {devices/lab_pin.sym} 290 740 3 0 {name=p142 sig_type=std_logic lab=VSS}
C {devices/lab_pin.sym} 410 740 3 0 {name=p156 sig_type=std_logic lab=VSS}
C {devices/lab_pin.sym} 530 740 3 0 {name=p157 sig_type=std_logic lab=VSS}
C {devices/lab_pin.sym} 650 740 3 0 {name=p158 sig_type=std_logic lab=VSS}
C {devices/lab_pin.sym} 770 740 3 0 {name=p159 sig_type=std_logic lab=VSS}
C {devices/lab_pin.sym} 890 740 3 0 {name=p160 sig_type=std_logic lab=VSS}
C {devices/lab_pin.sym} 1010 740 3 0 {name=p161 sig_type=std_logic lab=VSS}
C {devices/lab_pin.sym} 1130 740 3 0 {name=p162 sig_type=std_logic lab=VSS}
C {devices/lab_pin.sym} 1250 740 3 0 {name=p163 sig_type=std_logic lab=VSS}
C {devices/lab_pin.sym} 1370 740 3 0 {name=p164 sig_type=std_logic lab=VSS}
C {devices/lab_pin.sym} 1490 740 3 0 {name=p165 sig_type=std_logic lab=VSS}
C {devices/lab_pin.sym} 1610 740 3 0 {name=p166 sig_type=std_logic lab=VSS}
C {devices/lab_pin.sym} 1730 740 3 0 {name=p167 sig_type=std_logic lab=VSS}
C {devices/lab_pin.sym} 1850 740 3 0 {name=p168 sig_type=std_logic lab=VSS}
C {devices/lab_pin.sym} 1970 740 3 0 {name=p169 sig_type=std_logic lab=VSS}
C {devices/lab_pin.sym} 2090 740 3 0 {name=p170 sig_type=std_logic lab=VSS}
C {devices/lab_pin.sym} 300 530 3 0 {name=p187 sig_type=std_logic lab=VSS}
C {devices/lab_pin.sym} 420 530 3 0 {name=p188 sig_type=std_logic lab=VSS}
C {devices/lab_pin.sym} 540 530 3 0 {name=p189 sig_type=std_logic lab=VSS}
C {devices/lab_pin.sym} 660 530 3 0 {name=p190 sig_type=std_logic lab=VSS}
C {devices/lab_pin.sym} 780 530 3 0 {name=p191 sig_type=std_logic lab=VSS}
C {devices/lab_pin.sym} 900 530 3 0 {name=p192 sig_type=std_logic lab=VSS}
C {devices/lab_pin.sym} 1020 530 3 0 {name=p193 sig_type=std_logic lab=VSS}
C {devices/lab_pin.sym} 1140 530 3 0 {name=p194 sig_type=std_logic lab=VSS}
C {devices/lab_pin.sym} 1260 530 3 0 {name=p195 sig_type=std_logic lab=VSS}
C {devices/lab_pin.sym} 1380 530 3 0 {name=p196 sig_type=std_logic lab=VSS}
C {devices/lab_pin.sym} 1500 530 3 0 {name=p197 sig_type=std_logic lab=VSS}
C {devices/lab_pin.sym} 1620 530 3 0 {name=p198 sig_type=std_logic lab=VSS}
C {devices/lab_pin.sym} 1740 530 3 0 {name=p199 sig_type=std_logic lab=VSS}
C {devices/lab_pin.sym} 1860 530 3 0 {name=p200 sig_type=std_logic lab=VSS}
C {devices/lab_pin.sym} 1980 530 3 0 {name=p201 sig_type=std_logic lab=VSS}
C {devices/lab_pin.sym} 2100 530 3 0 {name=p202 sig_type=std_logic lab=VSS}
C {devices/lab_pin.sym} 260 630 1 0 {name=p203 sig_type=std_logic lab=VDD}
C {devices/lab_pin.sym} 380 630 1 0 {name=p204 sig_type=std_logic lab=VDD}
C {devices/lab_pin.sym} 500 630 1 0 {name=p205 sig_type=std_logic lab=VDD}
C {devices/lab_pin.sym} 620 630 1 0 {name=p206 sig_type=std_logic lab=VDD}
C {devices/lab_pin.sym} 740 630 1 0 {name=p207 sig_type=std_logic lab=VDD}
C {devices/lab_pin.sym} 860 630 1 0 {name=p208 sig_type=std_logic lab=VDD}
C {devices/lab_pin.sym} 980 630 1 0 {name=p209 sig_type=std_logic lab=VDD}
C {devices/lab_pin.sym} 1100 630 1 0 {name=p210 sig_type=std_logic lab=VDD}
C {devices/lab_pin.sym} 1700 630 1 0 {name=p211 sig_type=std_logic lab=VDD}
C {devices/lab_pin.sym} 1820 630 1 0 {name=p212 sig_type=std_logic lab=VDD}
C {devices/lab_pin.sym} 1940 630 1 0 {name=p213 sig_type=std_logic lab=VDD}
C {devices/lab_pin.sym} 2060 630 1 0 {name=p214 sig_type=std_logic lab=VDD}
C {devices/lab_pin.sym} 1220 630 1 0 {name=p215 sig_type=std_logic lab=VDD}
C {devices/lab_pin.sym} 1340 630 1 0 {name=p216 sig_type=std_logic lab=VDD}
C {devices/lab_pin.sym} 1460 630 1 0 {name=p217 sig_type=std_logic lab=VDD}
C {devices/lab_pin.sym} 1580 630 1 0 {name=p218 sig_type=std_logic lab=VDD}
C {devices/noconn.sym} 210 220 2 0 {name=l1}
C {devices/noconn.sym} 330 220 2 0 {name=l2}
C {devices/noconn.sym} 450 220 2 0 {name=l3}
C {devices/noconn.sym} 570 220 2 0 {name=l4}
C {devices/noconn.sym} 690 220 2 0 {name=l5}
C {devices/noconn.sym} 810 220 2 0 {name=l6}
C {devices/noconn.sym} 930 220 2 0 {name=l7}
C {devices/noconn.sym} 1050 220 2 0 {name=l8}
C {devices/noconn.sym} 1170 220 2 0 {name=l9}
C {devices/noconn.sym} 1290 220 2 0 {name=l10}
C {devices/noconn.sym} 1410 220 2 0 {name=l11}
C {devices/noconn.sym} 1530 220 2 0 {name=l12}
C {devices/noconn.sym} 1650 220 2 0 {name=l13}
C {devices/noconn.sym} 1770 220 2 0 {name=l14}
C {devices/noconn.sym} 1890 220 2 0 {name=l15}
C {devices/noconn.sym} 2010 220 2 0 {name=l16}
C {devices/noconn.sym} 2120 700 2 0 {name=l17}
C {devices/noconn.sym} 2000 700 2 0 {name=l18}
C {devices/noconn.sym} 1880 700 2 0 {name=l19}
C {devices/noconn.sym} 1760 700 2 0 {name=l20}
C {devices/noconn.sym} 1640 700 2 0 {name=l21}
C {devices/noconn.sym} 1520 700 2 0 {name=l22}
C {devices/noconn.sym} 1400 700 2 0 {name=l23}
C {devices/noconn.sym} 1280 700 2 0 {name=l24}
C {devices/noconn.sym} 1160 700 2 0 {name=l25}
C {devices/noconn.sym} 1040 700 2 0 {name=l26}
C {devices/noconn.sym} 920 700 2 0 {name=l27}
C {devices/noconn.sym} 800 700 2 0 {name=l28}
C {devices/noconn.sym} 560 700 2 0 {name=l29}
C {devices/noconn.sym} 440 700 2 0 {name=l30}
C {devices/noconn.sym} 320 700 2 0 {name=l31}
C {devices/noconn.sym} 680 700 2 0 {name=l32}
C {devices/lab_pin.sym} 120 120 1 0 {name=p8 sig_type=std_logic lab=dly0}
C {devices/lab_pin.sym} 240 120 1 0 {name=p27 sig_type=std_logic lab=dly1}
C {devices/lab_pin.sym} 360 120 1 0 {name=p28 sig_type=std_logic lab=dly2}
C {devices/lab_pin.sym} 480 120 1 0 {name=p29 sig_type=std_logic lab=dly3}
C {devices/lab_pin.sym} 220 400 1 0 {name=p30 sig_type=std_logic lab=q0}
C {devices/lab_pin.sym} 340 400 1 0 {name=p31 sig_type=std_logic lab=q1}
C {devices/lab_pin.sym} 460 400 1 0 {name=p32 sig_type=std_logic lab=q2}
C {devices/lab_pin.sym} 580 400 1 0 {name=p33 sig_type=std_logic lab=q3}
C {devices/lab_pin.sym} 350 600 1 0 {name=p34 sig_type=std_logic lab=s0}
C {devices/lab_pin.sym} 470 600 1 0 {name=p35 sig_type=std_logic lab=s1}
C {devices/lab_pin.sym} 590 600 1 0 {name=p36 sig_type=std_logic lab=s2}
C {devices/lab_pin.sym} 710 600 1 0 {name=p37 sig_type=std_logic lab=s3}
